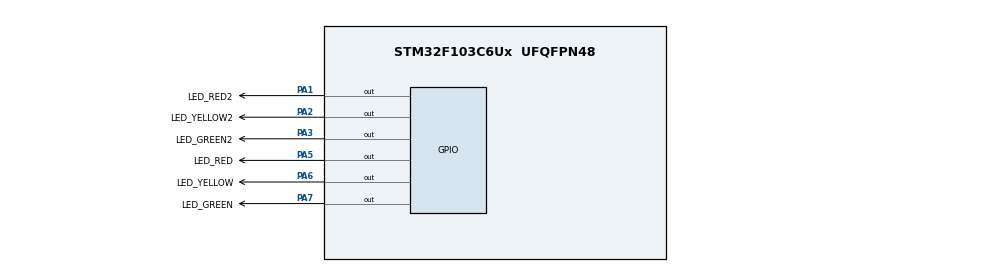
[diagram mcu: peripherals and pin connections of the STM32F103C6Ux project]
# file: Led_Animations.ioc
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Mcu.Family=STM32F1
Mcu.Name=STM32F103C6Ux
Mcu.Package=UFQFPN48
NVIC.PriorityGroup=NVIC_PRIORITYGROUP_4
PA1.GPIO_Label=LED_RED2
PA1.Signal=GPIO_Output
PA2.GPIO_Label=LED_YELLOW2
PA2.Signal=GPIO_Output
PA3.GPIO_Label=LED_GREEN2
PA3.Signal=GPIO_Output
PA5.GPIO_Label=LED_RED
PA5.Signal=GPIO_Output
PA6.GPIO_Label=LED_YELLOW
PA6.Signal=GPIO_Output
PA7.GPIO_Label=LED_GREEN
PA7.Signal=GPIO_Output
ProjectManager.HeapSize=0x200
ProjectManager.StackSize=0x400
ProjectManager.TargetToolchain=STM32CubeIDE
RCC.APB1Freq_Value=8000000
RCC.APB2Freq_Value=8000000
VP_SYS_VS_ND.Mode=No_Debug
board=custom

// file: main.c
/* USER CODE BEGIN Header */
/**
  ******************************************************************************
  * @file           : main.c
  * @brief          : Main program body
  ******************************************************************************
  * @attention
  *
  * <h2><center>&copy; Copyright (c) 2025 STMicroelectronics.
  * All rights reserved.</center></h2>
  *
  * This software component is licensed by ST under BSD 3-Clause license,
  * the "License"; You may not use this file except in compliance with the
  * License. You may obtain a copy of the License at:
  *                        opensource.org/licenses/BSD-3-Clause
  *
  ******************************************************************************
  */
/* USER CODE END Header */
#include "main.h"

void SystemClock_Config(void);
static void MX_GPIO_Init(void);

int main(void)
{

  /* MCU Configuration--------------------------------------------------------*/

  /* Reset of all peripherals, Initializes the Flash interface and the Systick. */
  HAL_Init();

  /* Configure the system clock */
  SystemClock_Config();

  /* Initialize all configured peripherals */
  MX_GPIO_Init();

  /* Infinite loop */
  /* USER CODE BEGIN WHILE */

  void display7SEG(int num) {
        // Mã LED 7 đoạn dạng cathode chung (0 = bật, 1 = tắt)
        uint8_t segNumber[10] = {
            0xC0, // 0
            0xF9, // 1
            0xA4, // 2
            0xB0, // 3
            0x99, // 4
            0x92, // 5
            0x82, // 6
            0xF8, // 7
            0x80, // 8
            0x90  // 9
        };

        // Lần lượt ghi tín hiệu ra 7 chân tương ứng A -> G
        // Giả sử các chân nối với GPIOB PIN_0 đến PIN_6
        for (int i = 0; i < 7; ++i)
           HAL_GPIO_WritePin(GPIOB, GPIO_PIN_0 << i, (segNumber[num] >> i) & 0x01 ? GPIO_PIN_SET : GPIO_PIN_RESET);
    }
  int counter =0;
  while (1)
  {
    /* USER CODE END WHILE */
	  if(counter >= 10) counter = 0;
	   display7SEG(counter++);
	   HAL_Delay(1000);
  }
}

void SystemClock_Config(void)
{
  RCC_OscInitTypeDef RCC_OscInitStruct = {0};
  RCC_ClkInitTypeDef RCC_ClkInitStruct = {0};

  /** Initializes the RCC Oscillators according to the specified parameters
  * in the RCC_OscInitTypeDef structure.
  */
  RCC_OscInitStruct.OscillatorType = RCC_OSCILLATORTYPE_HSI;
  RCC_OscInitStruct.HSIState = RCC_HSI_ON;
  RCC_OscInitStruct.HSICalibrationValue = RCC_HSICALIBRATION_DEFAULT;
  RCC_OscInitStruct.PLL.PLLState = RCC_PLL_NONE;
  if (HAL_RCC_OscConfig(&RCC_OscInitStruct) != HAL_OK)
  {
    Error_Handler();
  }
  /** Initializes the CPU, AHB and APB buses clocks
  */
  RCC_ClkInitStruct.ClockType = RCC_CLOCKTYPE_HCLK|RCC_CLOCKTYPE_SYSCLK
                              |RCC_CLOCKTYPE_PCLK1|RCC_CLOCKTYPE_PCLK2;
  RCC_ClkInitStruct.SYSCLKSource = RCC_SYSCLKSOURCE_HSI;
  RCC_ClkInitStruct.AHBCLKDivider = RCC_SYSCLK_DIV1;
  RCC_ClkInitStruct.APB1CLKDivider = RCC_HCLK_DIV1;
  RCC_ClkInitStruct.APB2CLKDivider = RCC_HCLK_DIV1;

  if (HAL_RCC_ClockConfig(&RCC_ClkInitStruct, FLASH_LATENCY_0) != HAL_OK)
  {
    Error_Handler();
  }
}

static void MX_GPIO_Init(void)
{
  GPIO_InitTypeDef GPIO_InitStruct = {0};

  /* GPIO Ports Clock Enable */
  __HAL_RCC_GPIOB_CLK_ENABLE();

  /*Configure GPIO pin Output Level */
  HAL_GPIO_WritePin(GPIOB, GPIO_PIN_0|GPIO_PIN_1|GPIO_PIN_2|GPIO_PIN_3
                          |GPIO_PIN_4|GPIO_PIN_5|GPIO_PIN_6, GPIO_PIN_RESET);

  /*Configure GPIO pins : PB0 PB1 PB2 PB3
                           PB4 PB5 PB6 */
  GPIO_InitStruct.Pin = GPIO_PIN_0|GPIO_PIN_1|GPIO_PIN_2|GPIO_PIN_3
                          |GPIO_PIN_4|GPIO_PIN_5|GPIO_PIN_6;
  GPIO_InitStruct.Mode = GPIO_MODE_OUTPUT_PP;
  GPIO_InitStruct.Pull = GPIO_NOPULL;
  GPIO_InitStruct.Speed = GPIO_SPEED_FREQ_LOW;
  HAL_GPIO_Init(GPIOB, &GPIO_InitStruct);

}

void Error_Handler(void)
{
  __disable_irq();
  while (1)
  {
  }
}

/************************ (C) COPYRIGHT STMicroelectronics *****END OF FILE****/
